VERSION 5.8 ;
BUSBITCHARS "[]" ;
DIVIDERCHAR "/" ;

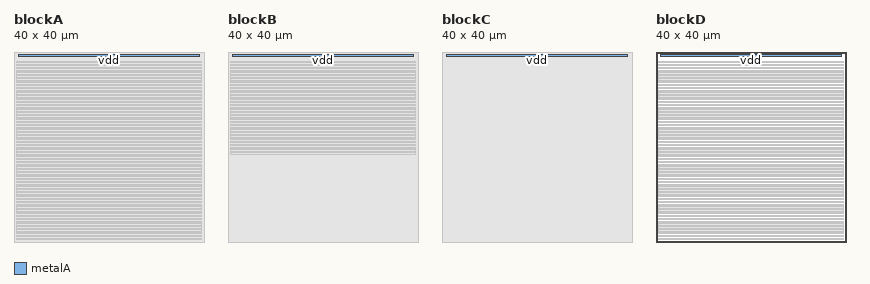
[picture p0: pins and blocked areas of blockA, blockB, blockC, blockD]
MACRO blockA
  CLASS BLOCK ;
  ORIGIN 0.000 0.000 ;
  SIZE 40.000 BY 40.000 ;
  SYMMETRY X Y R90 ;
  PIN vdd
    DIRECTION INOUT ;
    USE POWER ;
    PORT
      LAYER metalA ;
        RECT 1.000 39.000 39.000 39.400 ;
    END
  END vdd
  OBS
    LAYER OVERLAP ;
      RECT 0.000 0.000 40.000 40.000 ;
    LAYER metalA ;
      RECT 0.500 0.500 39.500 0.800 ;
      RECT 0.500 1.100 39.500 1.400 ;
      RECT 0.500 1.700 39.500 2.000 ;
      RECT 0.500 2.300 39.500 2.600 ;
      RECT 0.500 2.900 39.500 3.200 ;
      RECT 0.500 3.500 39.500 3.800 ;
      RECT 0.500 4.100 39.500 4.400 ;
      RECT 0.500 4.700 39.500 5.000 ;
      RECT 0.500 5.300 39.500 5.600 ;
      RECT 0.500 5.900 39.500 6.200 ;
      RECT 0.500 6.500 39.500 6.800 ;
      RECT 0.500 7.100 39.500 7.400 ;
      RECT 0.500 7.700 39.500 8.000 ;
      RECT 0.500 8.300 39.500 8.600 ;
      RECT 0.500 8.900 39.500 9.200 ;
      RECT 0.500 9.500 39.500 9.800 ;
      RECT 0.500 10.100 39.500 10.400 ;
      RECT 0.500 10.700 39.500 11.000 ;
      RECT 0.500 11.300 39.500 11.600 ;
      RECT 0.500 11.900 39.500 12.200 ;
      RECT 0.500 12.500 39.500 12.800 ;
      RECT 0.500 13.100 39.500 13.400 ;
      RECT 0.500 13.700 39.500 14.000 ;
      RECT 0.500 14.300 39.500 14.600 ;
      RECT 0.500 14.900 39.500 15.200 ;
      RECT 0.500 15.500 39.500 15.800 ;
      RECT 0.500 16.100 39.500 16.400 ;
      RECT 0.500 16.700 39.500 17.000 ;
      RECT 0.500 17.300 39.500 17.600 ;
      RECT 0.500 17.900 39.500 18.200 ;
      RECT 0.500 18.500 39.500 18.800 ;
      RECT 0.500 19.100 39.500 19.400 ;
      RECT 0.500 19.700 39.500 20.000 ;
      RECT 0.500 20.300 39.500 20.600 ;
      RECT 0.500 20.900 39.500 21.200 ;
      RECT 0.500 21.500 39.500 21.800 ;
      RECT 0.500 22.100 39.500 22.400 ;
      RECT 0.500 22.700 39.500 23.000 ;
      RECT 0.500 23.300 39.500 23.600 ;
      RECT 0.500 23.900 39.500 24.200 ;
      RECT 0.500 24.500 39.500 24.800 ;
      RECT 0.500 25.100 39.500 25.400 ;
      RECT 0.500 25.700 39.500 26.000 ;
      RECT 0.500 26.300 39.500 26.600 ;
      RECT 0.500 26.900 39.500 27.200 ;
      RECT 0.500 27.500 39.500 27.800 ;
      RECT 0.500 28.100 39.500 28.400 ;
      RECT 0.500 28.700 39.500 29.000 ;
      RECT 0.500 29.300 39.500 29.600 ;
      RECT 0.500 29.900 39.500 30.200 ;
      RECT 0.500 30.500 39.500 30.800 ;
      RECT 0.500 31.100 39.500 31.400 ;
      RECT 0.500 31.700 39.500 32.000 ;
      RECT 0.500 32.300 39.500 32.600 ;
      RECT 0.500 32.900 39.500 33.200 ;
      RECT 0.500 33.500 39.500 33.800 ;
      RECT 0.500 34.100 39.500 34.400 ;
      RECT 0.500 34.700 39.500 35.000 ;
      RECT 0.500 35.300 39.500 35.600 ;
      RECT 0.500 35.900 39.500 36.200 ;
      RECT 0.500 36.500 39.500 36.800 ;
      RECT 0.500 37.100 39.500 37.400 ;
      RECT 0.500 37.700 39.500 38.000 ;
  END
END blockA

MACRO blockB
  CLASS BLOCK ;
  ORIGIN 0.000 0.000 ;
  SIZE 40.000 BY 40.000 ;
  SYMMETRY X Y R90 ;
  PIN vdd
    DIRECTION INOUT ;
    USE POWER ;
    PORT
      LAYER metalA ;
        RECT 1.000 39.000 39.000 39.400 ;
    END
  END vdd
  OBS
    LAYER metalA ;
      RECT 0.500 0.500 39.500 0.800 ;
      RECT 0.500 1.100 39.500 1.400 ;
      RECT 0.500 1.700 39.500 2.000 ;
      RECT 0.500 2.300 39.500 2.600 ;
      RECT 0.500 2.900 39.500 3.200 ;
      RECT 0.500 3.500 39.500 3.800 ;
      RECT 0.500 4.100 39.500 4.400 ;
      RECT 0.500 4.700 39.500 5.000 ;
      RECT 0.500 5.300 39.500 5.600 ;
      RECT 0.500 5.900 39.500 6.200 ;
      RECT 0.500 6.500 39.500 6.800 ;
      RECT 0.500 7.100 39.500 7.400 ;
      RECT 0.500 7.700 39.500 8.000 ;
      RECT 0.500 8.300 39.500 8.600 ;
      RECT 0.500 8.900 39.500 9.200 ;
      RECT 0.500 9.500 39.500 9.800 ;
      RECT 0.500 10.100 39.500 10.400 ;
      RECT 0.500 10.700 39.500 11.000 ;
      RECT 0.500 11.300 39.500 11.600 ;
      RECT 0.500 11.900 39.500 12.200 ;
      RECT 0.500 12.500 39.500 12.800 ;
      RECT 0.500 13.100 39.500 13.400 ;
      RECT 0.500 13.700 39.500 14.000 ;
      RECT 0.500 14.300 39.500 14.600 ;
      RECT 0.500 14.900 39.500 15.200 ;
      RECT 0.500 15.500 39.500 15.800 ;
      RECT 0.500 16.100 39.500 16.400 ;
      RECT 0.500 16.700 39.500 17.000 ;
      RECT 0.500 17.300 39.500 17.600 ;
      RECT 0.500 17.900 39.500 18.200 ;
    LAYER OVERLAP ;
      RECT 0.000 0.000 40.000 40.000 ;
    LAYER metalA ;
      RECT 0.500 18.500 39.500 18.800 ;
      RECT 0.500 19.100 39.500 19.400 ;
      RECT 0.500 19.700 39.500 20.000 ;
      RECT 0.500 20.300 39.500 20.600 ;
      RECT 0.500 20.900 39.500 21.200 ;
      RECT 0.500 21.500 39.500 21.800 ;
      RECT 0.500 22.100 39.500 22.400 ;
      RECT 0.500 22.700 39.500 23.000 ;
      RECT 0.500 23.300 39.500 23.600 ;
      RECT 0.500 23.900 39.500 24.200 ;
      RECT 0.500 24.500 39.500 24.800 ;
      RECT 0.500 25.100 39.500 25.400 ;
      RECT 0.500 25.700 39.500 26.000 ;
      RECT 0.500 26.300 39.500 26.600 ;
      RECT 0.500 26.900 39.500 27.200 ;
      RECT 0.500 27.500 39.500 27.800 ;
      RECT 0.500 28.100 39.500 28.400 ;
      RECT 0.500 28.700 39.500 29.000 ;
      RECT 0.500 29.300 39.500 29.600 ;
      RECT 0.500 29.900 39.500 30.200 ;
      RECT 0.500 30.500 39.500 30.800 ;
      RECT 0.500 31.100 39.500 31.400 ;
      RECT 0.500 31.700 39.500 32.000 ;
      RECT 0.500 32.300 39.500 32.600 ;
      RECT 0.500 32.900 39.500 33.200 ;
      RECT 0.500 33.500 39.500 33.800 ;
      RECT 0.500 34.100 39.500 34.400 ;
      RECT 0.500 34.700 39.500 35.000 ;
      RECT 0.500 35.300 39.500 35.600 ;
      RECT 0.500 35.900 39.500 36.200 ;
      RECT 0.500 36.500 39.500 36.800 ;
      RECT 0.500 37.100 39.500 37.400 ;
      RECT 0.500 37.700 39.500 38.000 ;
  END
END blockB

MACRO blockC
  CLASS BLOCK ;
  ORIGIN 0.000 0.000 ;
  SIZE 40.000 BY 40.000 ;
  SYMMETRY X Y R90 ;
  PIN vdd
    DIRECTION INOUT ;
    USE POWER ;
    PORT
      LAYER metalA ;
        RECT 1.000 39.000 39.000 39.400 ;
    END
  END vdd
  OBS
    LAYER metalA ;
      RECT 0.500 0.500 39.500 0.800 ;
      RECT 0.500 1.100 39.500 1.400 ;
      RECT 0.500 1.700 39.500 2.000 ;
      RECT 0.500 2.300 39.500 2.600 ;
      RECT 0.500 2.900 39.500 3.200 ;
      RECT 0.500 3.500 39.500 3.800 ;
      RECT 0.500 4.100 39.500 4.400 ;
      RECT 0.500 4.700 39.500 5.000 ;
      RECT 0.500 5.300 39.500 5.600 ;
      RECT 0.500 5.900 39.500 6.200 ;
      RECT 0.500 6.500 39.500 6.800 ;
      RECT 0.500 7.100 39.500 7.400 ;
      RECT 0.500 7.700 39.500 8.000 ;
      RECT 0.500 8.300 39.500 8.600 ;
      RECT 0.500 8.900 39.500 9.200 ;
      RECT 0.500 9.500 39.500 9.800 ;
      RECT 0.500 10.100 39.500 10.400 ;
      RECT 0.500 10.700 39.500 11.000 ;
      RECT 0.500 11.300 39.500 11.600 ;
      RECT 0.500 11.900 39.500 12.200 ;
      RECT 0.500 12.500 39.500 12.800 ;
      RECT 0.500 13.100 39.500 13.400 ;
      RECT 0.500 13.700 39.500 14.000 ;
      RECT 0.500 14.300 39.500 14.600 ;
      RECT 0.500 14.900 39.500 15.200 ;
      RECT 0.500 15.500 39.500 15.800 ;
      RECT 0.500 16.100 39.500 16.400 ;
      RECT 0.500 16.700 39.500 17.000 ;
      RECT 0.500 17.300 39.500 17.600 ;
      RECT 0.500 17.900 39.500 18.200 ;
      RECT 0.500 18.500 39.500 18.800 ;
      RECT 0.500 19.100 39.500 19.400 ;
      RECT 0.500 19.700 39.500 20.000 ;
      RECT 0.500 20.300 39.500 20.600 ;
      RECT 0.500 20.900 39.500 21.200 ;
      RECT 0.500 21.500 39.500 21.800 ;
      RECT 0.500 22.100 39.500 22.400 ;
      RECT 0.500 22.700 39.500 23.000 ;
      RECT 0.500 23.300 39.500 23.600 ;
      RECT 0.500 23.900 39.500 24.200 ;
      RECT 0.500 24.500 39.500 24.800 ;
      RECT 0.500 25.100 39.500 25.400 ;
      RECT 0.500 25.700 39.500 26.000 ;
      RECT 0.500 26.300 39.500 26.600 ;
      RECT 0.500 26.900 39.500 27.200 ;
      RECT 0.500 27.500 39.500 27.800 ;
      RECT 0.500 28.100 39.500 28.400 ;
      RECT 0.500 28.700 39.500 29.000 ;
      RECT 0.500 29.300 39.500 29.600 ;
      RECT 0.500 29.900 39.500 30.200 ;
      RECT 0.500 30.500 39.500 30.800 ;
      RECT 0.500 31.100 39.500 31.400 ;
      RECT 0.500 31.700 39.500 32.000 ;
      RECT 0.500 32.300 39.500 32.600 ;
      RECT 0.500 32.900 39.500 33.200 ;
      RECT 0.500 33.500 39.500 33.800 ;
      RECT 0.500 34.100 39.500 34.400 ;
      RECT 0.500 34.700 39.500 35.000 ;
      RECT 0.500 35.300 39.500 35.600 ;
      RECT 0.500 35.900 39.500 36.200 ;
      RECT 0.500 36.500 39.500 36.800 ;
      RECT 0.500 37.100 39.500 37.400 ;
      RECT 0.500 37.700 39.500 38.000 ;
    LAYER OVERLAP ;
      RECT 0.000 0.000 40.000 40.000 ;
  END
END blockC

MACRO blockD
  CLASS BLOCK ;
  ORIGIN 0.000 0.000 ;
  SIZE 40.000 BY 40.000 ;
  SYMMETRY X Y R90 ;
  PIN vdd
    DIRECTION INOUT ;
    USE POWER ;
    PORT
      LAYER metalA ;
        RECT 1.000 39.000 39.000 39.400 ;
    END
  END vdd
  OBS
    LAYER metalA ;
      RECT 0.500 0.500 39.500 0.800 ;
      RECT 0.500 1.100 39.500 1.400 ;
      RECT 0.500 1.700 39.500 2.000 ;
      RECT 0.500 2.300 39.500 2.600 ;
      RECT 0.500 2.900 39.500 3.200 ;
      RECT 0.500 3.500 39.500 3.800 ;
      RECT 0.500 4.100 39.500 4.400 ;
      RECT 0.500 4.700 39.500 5.000 ;
      RECT 0.500 5.300 39.500 5.600 ;
      RECT 0.500 5.900 39.500 6.200 ;
      RECT 0.500 6.500 39.500 6.800 ;
      RECT 0.500 7.100 39.500 7.400 ;
      RECT 0.500 7.700 39.500 8.000 ;
      RECT 0.500 8.300 39.500 8.600 ;
      RECT 0.500 8.900 39.500 9.200 ;
      RECT 0.500 9.500 39.500 9.800 ;
      RECT 0.500 10.100 39.500 10.400 ;
      RECT 0.500 10.700 39.500 11.000 ;
      RECT 0.500 11.300 39.500 11.600 ;
      RECT 0.500 11.900 39.500 12.200 ;
      RECT 0.500 12.500 39.500 12.800 ;
      RECT 0.500 13.100 39.500 13.400 ;
      RECT 0.500 13.700 39.500 14.000 ;
      RECT 0.500 14.300 39.500 14.600 ;
      RECT 0.500 14.900 39.500 15.200 ;
      RECT 0.500 15.500 39.500 15.800 ;
      RECT 0.500 16.100 39.500 16.400 ;
      RECT 0.500 16.700 39.500 17.000 ;
      RECT 0.500 17.300 39.500 17.600 ;
      RECT 0.500 17.900 39.500 18.200 ;
      VIA 20.000 20.000 undefinedVia ;
      RECT 0.500 18.500 39.500 18.800 ;
      RECT 0.500 19.100 39.500 19.400 ;
      RECT 0.500 19.700 39.500 20.000 ;
      RECT 0.500 20.300 39.500 20.600 ;
      RECT 0.500 20.900 39.500 21.200 ;
      RECT 0.500 21.500 39.500 21.800 ;
      RECT 0.500 22.100 39.500 22.400 ;
      RECT 0.500 22.700 39.500 23.000 ;
      RECT 0.500 23.300 39.500 23.600 ;
      RECT 0.500 23.900 39.500 24.200 ;
      RECT 0.500 24.500 39.500 24.800 ;
      RECT 0.500 25.100 39.500 25.400 ;
      RECT 0.500 25.700 39.500 26.000 ;
      RECT 0.500 26.300 39.500 26.600 ;
      RECT 0.500 26.900 39.500 27.200 ;
      RECT 0.500 27.500 39.500 27.800 ;
      RECT 0.500 28.100 39.500 28.400 ;
      RECT 0.500 28.700 39.500 29.000 ;
      RECT 0.500 29.300 39.500 29.600 ;
      RECT 0.500 29.900 39.500 30.200 ;
      RECT 0.500 30.500 39.500 30.800 ;
      RECT 0.500 31.100 39.500 31.400 ;
      RECT 0.500 31.700 39.500 32.000 ;
      RECT 0.500 32.300 39.500 32.600 ;
      RECT 0.500 32.900 39.500 33.200 ;
      RECT 0.500 33.500 39.500 33.800 ;
      RECT 0.500 34.100 39.500 34.400 ;
      RECT 0.500 34.700 39.500 35.000 ;
      RECT 0.500 35.300 39.500 35.600 ;
      RECT 0.500 35.900 39.500 36.200 ;
      RECT 0.500 36.500 39.500 36.800 ;
      RECT 0.500 37.100 39.500 37.400 ;
      RECT 0.500 37.700 39.500 38.000 ;
  END
END blockD

END LIBRARY
